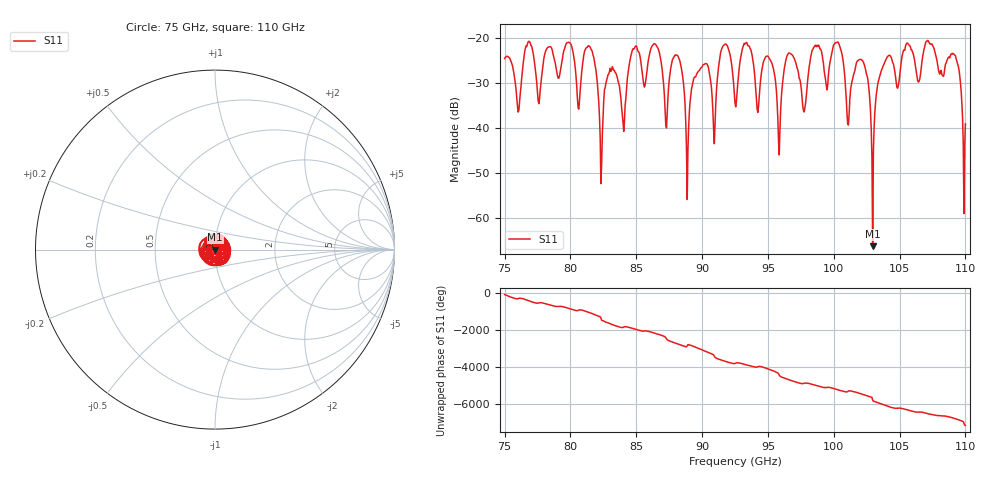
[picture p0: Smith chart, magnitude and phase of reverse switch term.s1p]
!Created with skrf (http://scikit-rf.org).
# GHz S RI R 50.0
!freq ReS11 ImS11
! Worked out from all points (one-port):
!   647 points, 75 GHz to 110 GHz, reference 50 ohm
!   lowest |S11| = -66.2 dB at 103 GHz (marker M1), VSWR 1.00, Z = 50 - j0.0314 ohm
!   |S11| at or under -10 dB: start of sweep to end of sweep
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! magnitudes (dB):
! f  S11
! 75 GHz  -24.6
! 76.03 GHz  -36.4
! 76.79 GHz  -20.8
! 79.39 GHz  -24.7
! 81.56 GHz  -22.4
! 82.32 GHz  -52.3
! 82.91 GHz  -28.0
! 83.78 GHz  -32.1
! 86.43 GHz  -21.3
! 87.3 GHz  -40.0
! 88.17 GHz  -24.0
! 88.87 GHz  -55.9
! 90.12 GHz  -25.9
! 90.93 GHz  -43.5
! 91.69 GHz  -21.5
! 92.5 GHz  -34.4
! 94.99 GHz  -24.0
! 95.86 GHz  -46.0
! 96.89 GHz  -23.9
! 97.75 GHz  -36.4
! 100.3 GHz  -20.9
! 101.3 GHz  -31.5
! 102.2 GHz  -25.4
! 103 GHz  -66.2
! 103.6 GHz  -27.3
! 105.7 GHz  -21.4
! 109.2 GHz  -23.8
! 110 GHz  -39.1
